VERSION 5.7 ;
  NOWIREEXTENSIONATPIN ON ;
  DIVIDERCHAR "/" ;
  BUSBITCHARS "[]" ;
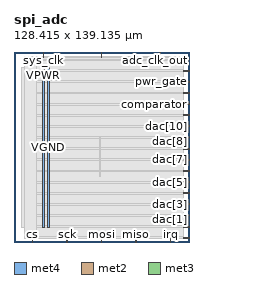
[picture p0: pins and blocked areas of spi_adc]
MACRO spi_adc
  CLASS BLOCK ;
  FOREIGN spi_adc ;
  ORIGIN 0.000 0.000 ;
  SIZE 128.415 BY 139.135 ;
  PIN VGND
    DIRECTION INOUT ;
    USE GROUND ;
    PORT
      LAYER met4 ;
        RECT 24.340 10.640 25.940 128.080 ;
    END
  END VGND
  PIN VPWR
    DIRECTION INOUT ;
    USE POWER ;
    PORT
      LAYER met4 ;
        RECT 21.040 10.640 22.640 128.080 ;
    END
  END VPWR
  PIN adc_clk_out
    DIRECTION OUTPUT ;
    USE SIGNAL ;
    ANTENNADIFFAREA 0.445500 ;
    PORT
      LAYER met2 ;
        RECT 106.810 135.135 107.090 139.135 ;
    END
  END adc_clk_out
  PIN comparator
    DIRECTION INPUT ;
    USE SIGNAL ;
    ANTENNAGATEAREA 0.196500 ;
    PORT
      LAYER met3 ;
        RECT 124.415 100.680 128.415 101.280 ;
    END
  END comparator
  PIN cs
    DIRECTION INPUT ;
    USE SIGNAL ;
    ANTENNAGATEAREA 0.196500 ;
    PORT
      LAYER met2 ;
        RECT 13.430 0.000 13.710 4.000 ;
    END
  END cs
  PIN dac[0]
    DIRECTION OUTPUT ;
    USE SIGNAL ;
    ANTENNADIFFAREA 0.445500 ;
    PORT
      LAYER met3 ;
        RECT 124.415 2.760 128.415 3.360 ;
    END
  END dac[0]
  PIN dac[10]
    DIRECTION OUTPUT ;
    USE SIGNAL ;
    ANTENNADIFFAREA 0.445500 ;
    PORT
      LAYER met3 ;
        RECT 124.415 84.360 128.415 84.960 ;
    END
  END dac[10]
  PIN dac[11]
    DIRECTION OUTPUT ;
    USE SIGNAL ;
    ANTENNADIFFAREA 0.445500 ;
    PORT
      LAYER met3 ;
        RECT 124.415 92.520 128.415 93.120 ;
    END
  END dac[11]
  PIN dac[1]
    DIRECTION OUTPUT ;
    USE SIGNAL ;
    ANTENNADIFFAREA 0.445500 ;
    PORT
      LAYER met3 ;
        RECT 124.415 10.920 128.415 11.520 ;
    END
  END dac[1]
  PIN dac[2]
    DIRECTION OUTPUT ;
    USE SIGNAL ;
    ANTENNADIFFAREA 0.445500 ;
    PORT
      LAYER met3 ;
        RECT 124.415 19.080 128.415 19.680 ;
    END
  END dac[2]
  PIN dac[3]
    DIRECTION OUTPUT ;
    USE SIGNAL ;
    ANTENNADIFFAREA 0.445500 ;
    PORT
      LAYER met3 ;
        RECT 124.415 27.240 128.415 27.840 ;
    END
  END dac[3]
  PIN dac[4]
    DIRECTION OUTPUT ;
    USE SIGNAL ;
    ANTENNADIFFAREA 0.445500 ;
    PORT
      LAYER met3 ;
        RECT 124.415 35.400 128.415 36.000 ;
    END
  END dac[4]
  PIN dac[5]
    DIRECTION OUTPUT ;
    USE SIGNAL ;
    ANTENNADIFFAREA 0.445500 ;
    PORT
      LAYER met3 ;
        RECT 124.415 43.560 128.415 44.160 ;
    END
  END dac[5]
  PIN dac[6]
    DIRECTION OUTPUT ;
    USE SIGNAL ;
    ANTENNADIFFAREA 0.445500 ;
    PORT
      LAYER met3 ;
        RECT 124.415 51.720 128.415 52.320 ;
    END
  END dac[6]
  PIN dac[7]
    DIRECTION OUTPUT ;
    USE SIGNAL ;
    ANTENNADIFFAREA 0.445500 ;
    PORT
      LAYER met3 ;
        RECT 124.415 59.880 128.415 60.480 ;
    END
  END dac[7]
  PIN dac[8]
    DIRECTION OUTPUT ;
    USE SIGNAL ;
    ANTENNADIFFAREA 0.445500 ;
    PORT
      LAYER met3 ;
        RECT 124.415 68.040 128.415 68.640 ;
    END
  END dac[8]
  PIN dac[9]
    DIRECTION OUTPUT ;
    USE SIGNAL ;
    ANTENNADIFFAREA 0.445500 ;
    PORT
      LAYER met3 ;
        RECT 124.415 76.200 128.415 76.800 ;
    END
  END dac[9]
  PIN dac_rst
    DIRECTION OUTPUT ;
    USE SIGNAL ;
    ANTENNADIFFAREA 0.445500 ;
    PORT
      LAYER met3 ;
        RECT 124.415 125.160 128.415 125.760 ;
    END
  END dac_rst
  PIN irq
    DIRECTION OUTPUT ;
    USE SIGNAL ;
    ANTENNADIFFAREA 0.445500 ;
    PORT
      LAYER met2 ;
        RECT 114.630 0.000 114.910 4.000 ;
    END
  END irq
  PIN miso
    DIRECTION OUTPUT ;
    USE SIGNAL ;
    ANTENNADIFFAREA 1.782000 ;
    PORT
      LAYER met2 ;
        RECT 89.330 0.000 89.610 4.000 ;
    END
  END miso
  PIN mosi
    DIRECTION INPUT ;
    USE SIGNAL ;
    ANTENNAGATEAREA 0.196500 ;
    PORT
      LAYER met2 ;
        RECT 64.030 0.000 64.310 4.000 ;
    END
  END mosi
  PIN pwr_gate
    DIRECTION OUTPUT ;
    USE SIGNAL ;
    ANTENNADIFFAREA 0.445500 ;
    PORT
      LAYER met3 ;
        RECT 124.415 117.000 128.415 117.600 ;
    END
  END pwr_gate
  PIN reset_
    DIRECTION INPUT ;
    USE SIGNAL ;
    ANTENNAGATEAREA 0.126000 ;
    PORT
      LAYER met2 ;
        RECT 64.030 135.135 64.310 139.135 ;
    END
  END reset_
  PIN sample_and_hold
    DIRECTION OUTPUT ;
    USE SIGNAL ;
    ANTENNADIFFAREA 0.445500 ;
    PORT
      LAYER met3 ;
        RECT 124.415 108.840 128.415 109.440 ;
    END
  END sample_and_hold
  PIN sck
    DIRECTION INPUT ;
    USE SIGNAL ;
    ANTENNAGATEAREA 0.196500 ;
    PORT
      LAYER met2 ;
        RECT 38.730 0.000 39.010 4.000 ;
    END
  END sck
  PIN sys_clk
    DIRECTION INPUT ;
    USE SIGNAL ;
    ANTENNAGATEAREA 0.852000 ;
    PORT
      LAYER met2 ;
        RECT 21.250 135.135 21.530 139.135 ;
    END
  END sys_clk
  PIN vref_sel
    DIRECTION OUTPUT ;
    USE SIGNAL ;
    ANTENNADIFFAREA 0.445500 ;
    PORT
      LAYER met3 ;
        RECT 124.415 133.320 128.415 133.920 ;
    END
  END vref_sel
  OBS
      LAYER nwell ;
        RECT 5.330 10.795 123.010 128.030 ;
      LAYER li1 ;
        RECT 5.520 10.795 122.820 127.925 ;
      LAYER met1 ;
        RECT 5.520 10.640 122.820 128.080 ;
      LAYER met2 ;
        RECT 7.920 134.855 20.970 135.730 ;
        RECT 21.810 134.855 63.750 135.730 ;
        RECT 64.590 134.855 106.530 135.730 ;
        RECT 107.370 134.855 121.350 135.730 ;
        RECT 7.920 4.280 121.350 134.855 ;
        RECT 7.920 2.875 13.150 4.280 ;
        RECT 13.990 2.875 38.450 4.280 ;
        RECT 39.290 2.875 63.750 4.280 ;
        RECT 64.590 2.875 89.050 4.280 ;
        RECT 89.890 2.875 114.350 4.280 ;
        RECT 115.190 2.875 121.350 4.280 ;
      LAYER met3 ;
        RECT 16.165 132.920 124.015 133.785 ;
        RECT 16.165 126.160 124.415 132.920 ;
        RECT 16.165 124.760 124.015 126.160 ;
        RECT 16.165 118.000 124.415 124.760 ;
        RECT 16.165 116.600 124.015 118.000 ;
        RECT 16.165 109.840 124.415 116.600 ;
        RECT 16.165 108.440 124.015 109.840 ;
        RECT 16.165 101.680 124.415 108.440 ;
        RECT 16.165 100.280 124.015 101.680 ;
        RECT 16.165 93.520 124.415 100.280 ;
        RECT 16.165 92.120 124.015 93.520 ;
        RECT 16.165 85.360 124.415 92.120 ;
        RECT 16.165 83.960 124.015 85.360 ;
        RECT 16.165 77.200 124.415 83.960 ;
        RECT 16.165 75.800 124.015 77.200 ;
        RECT 16.165 69.040 124.415 75.800 ;
        RECT 16.165 67.640 124.015 69.040 ;
        RECT 16.165 60.880 124.415 67.640 ;
        RECT 16.165 59.480 124.015 60.880 ;
        RECT 16.165 52.720 124.415 59.480 ;
        RECT 16.165 51.320 124.015 52.720 ;
        RECT 16.165 44.560 124.415 51.320 ;
        RECT 16.165 43.160 124.015 44.560 ;
        RECT 16.165 36.400 124.415 43.160 ;
        RECT 16.165 35.000 124.015 36.400 ;
        RECT 16.165 28.240 124.415 35.000 ;
        RECT 16.165 26.840 124.015 28.240 ;
        RECT 16.165 20.080 124.415 26.840 ;
        RECT 16.165 18.680 124.015 20.080 ;
        RECT 16.165 11.920 124.415 18.680 ;
        RECT 16.165 10.520 124.015 11.920 ;
        RECT 16.165 3.760 124.415 10.520 ;
        RECT 16.165 2.895 124.015 3.760 ;
      LAYER met4 ;
        RECT 62.855 47.775 63.185 76.665 ;
  END
END spi_adc
END LIBRARY

